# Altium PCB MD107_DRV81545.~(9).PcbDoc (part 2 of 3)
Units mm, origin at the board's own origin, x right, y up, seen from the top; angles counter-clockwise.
Board outline 152.45 x 74.46 mm, 4 copper layers (Top Layer, Mid-Layer 1, Mid-Layer 2, Bottom Layer), stack 2.355 mm thick; 223 components, 122 nets, 703 pads, 225 vias.
Unrouted connection lines stored in the file: 85.

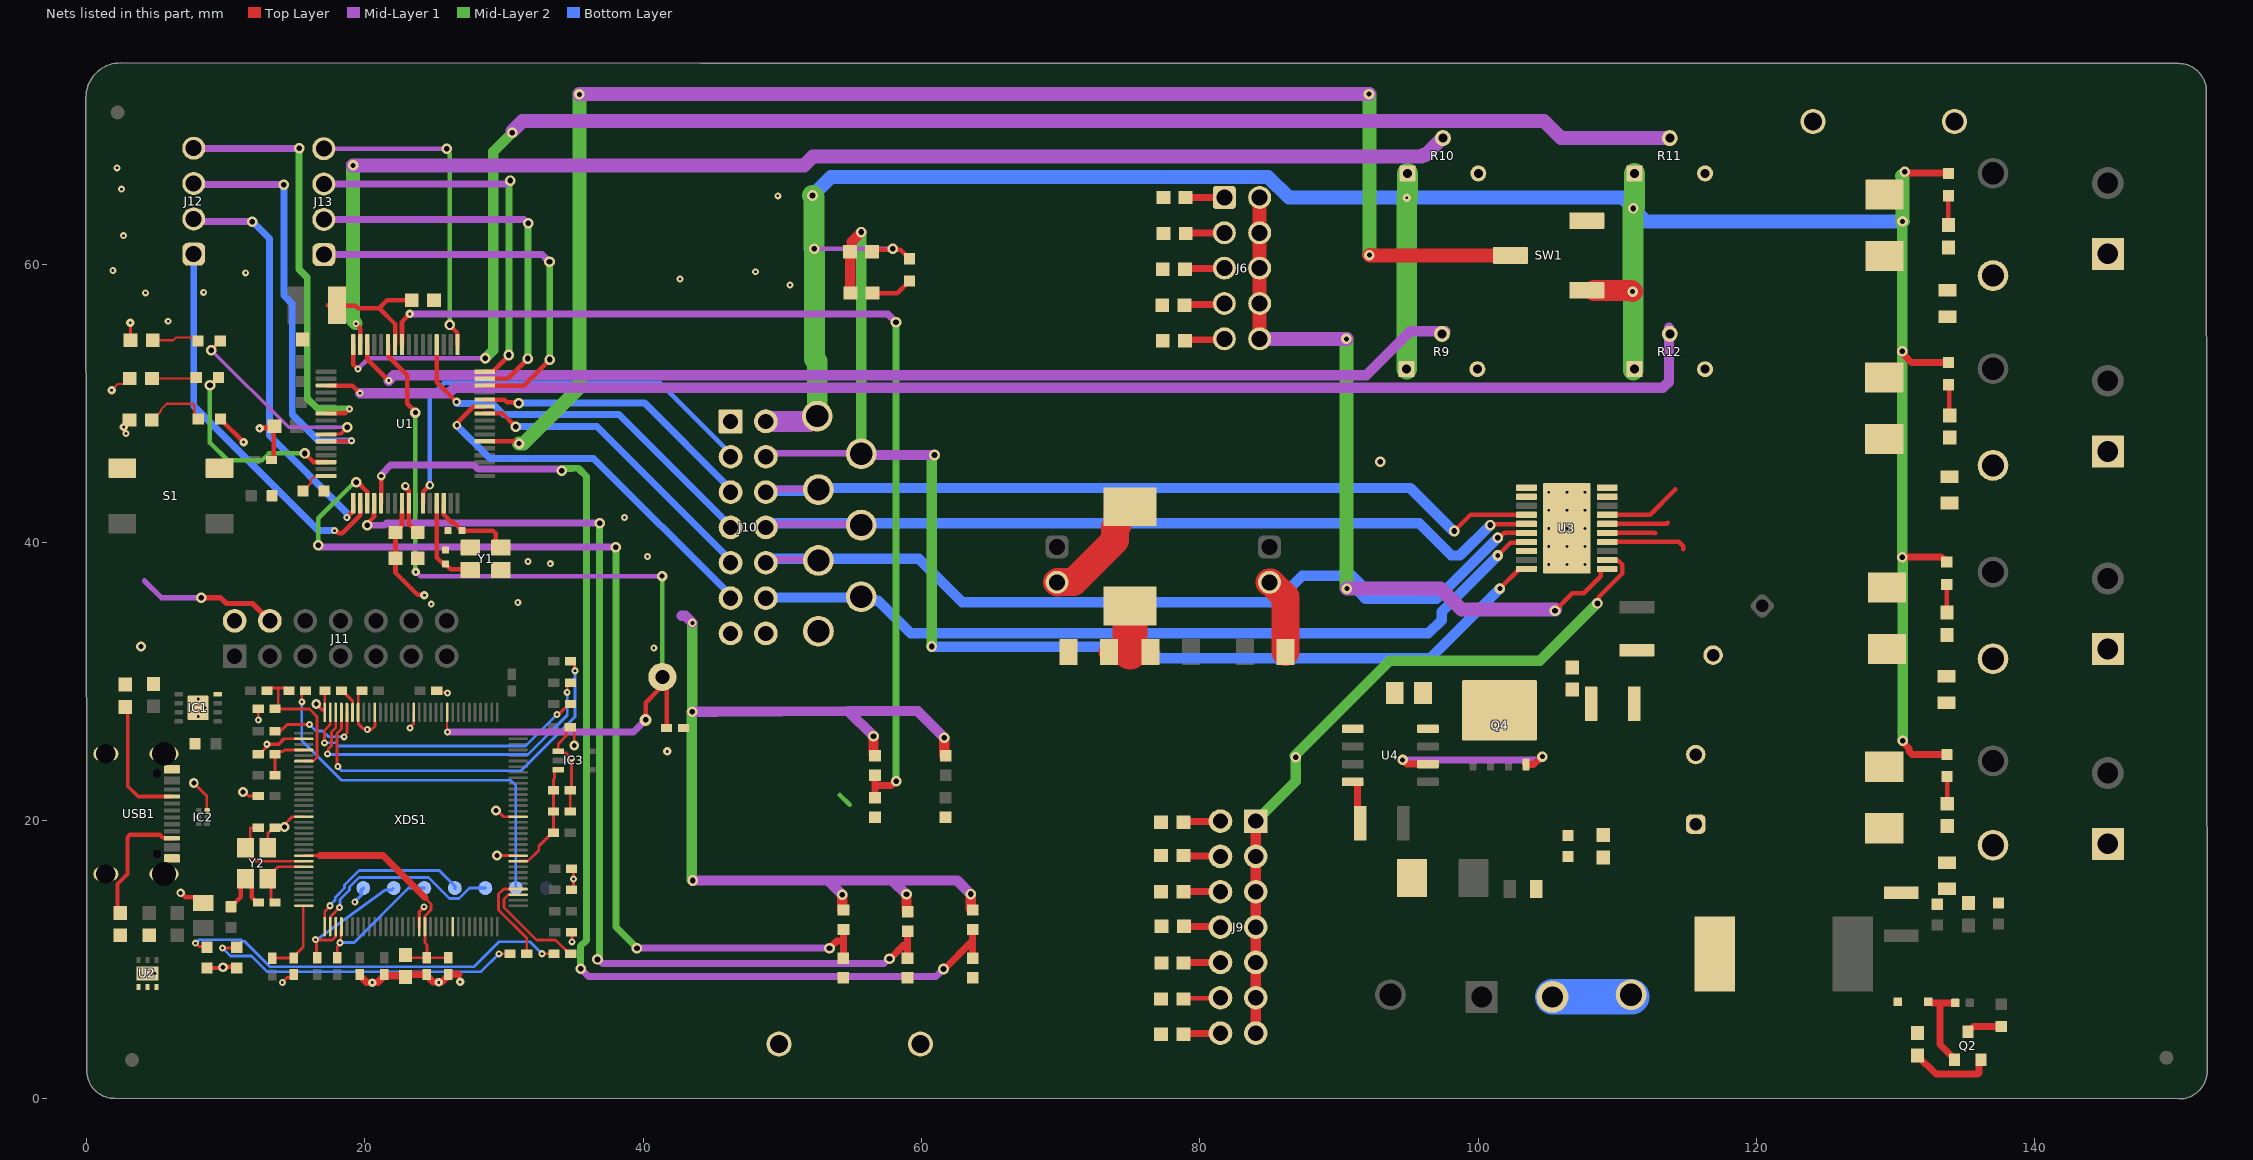
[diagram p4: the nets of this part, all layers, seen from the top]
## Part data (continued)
C50: library part CMP-0119409-1, "WCAP-CSGP Multilayer Ceramic Chip Capacitor, General Purpose, size 0603, X7R, 1nF, 100VDC", Capacitance Tolerance=+/-10%, Insulation Resistance=10GOhm, Manufacturer="Wurth Elektronik", Operating Temperature Max=125°C, Operating Temperature Min=-55°C, Rated Voltage (DC)=100V
D1 D2 D3 D13 D14 D15 D16 D18: library part CMP-0002894-2, "LED, Green, SMD", Color=green, Manufacturer="Wurth Elektronik", Value1=W, Value2=2V
D4: library part CMP-0078131-2, "LED, Red, SMD", Color=Red, Manufacturer=Lite-On, Power_TotalModule=62.5mW, Value1=.0625W, Value2=2V
D5: library part CMP-0002827-3, "LED, Green, SMD", Color=green, Manufacturer=Lite-On, Power_TotalModule=100mW, Value1=0.1W, Value2=2.1V
D6: library part CMP-0002947-3, "LED, Red, SMD", Color=Red, Manufacturer="Wurth Elektronik", Power_TotalModule=72mW, Value1=0.072W, Value2=2V
D7: library part CMP-0005695-3, "Diode, TVS, Bi, 33 V, SMC", Manufacturer=Bourns, Value1=1500W
D8: library part CMP-0005587-3, "Diode, TVS, Bi, 70 V, SMB", Manufacturer="Diodes Inc.", Value1=600W
D9 D10 D11 D12: library part CMP-0005564-3, "Diode, TVS, Bi, 33 V, SMB", Manufacturer="Diodes Inc.", Value1=600W
D17: library part CMP-14400-000003-2, "DIODE ZENER 4.7V 550MW SOD323F"
FID1 FID2 FID3: library part CMP-0077181-1, "Fiducial mark.  There is nothing to buy or mount.", Manufacturer=N/A
IC1: library part CMP-0036329-3, "500mA, Adjustable, Low Quiescent Current, Low-Noise, High-PSRR, Single-Output LDO Regulator, DRB0008A (VSON-8)", Manufacturer="Texas Instruments", Operating Temperature Range="-40 to 125 C", Rating=Catalog
IC2: library part CMP-0043115-3, "4-Channel ESD Protection Array for High-Speed Data Interfaces, DRY0006A (USON-6)", Breakdown Voltage(Min)(V)=6, IO Capacitance(Typ)(pF)=1.6, IO Leakage Current(nA)=1, Manufacturer="Texas Instruments", Operating Temperature Range="-40 to 85 C", Rating=Catalog
IC3: library part CMP-0032790-2, "Precision Micropower Shunt Voltage Reference, 0.5% accuracy, 2.5 V, 15 ppm / degC, 15 mA, -40 to 85 degC, 5-pin SC70 (DCK), Green (RoHS & no Sb/Br)", Manufacturer="Texas Instruments", Rating=Catalog, Temp Coeff(Max)(ppm/ degree C)=100, Temp Coeff(Typ)(ppm/ degree C)=15
J1 J2 J3 J4 J5: library part CMP-0121282-1, "2 Position Wire to Board Terminal Block Horizontal with Board 0.200\" (5.08mm) Through Hole", Current_A=20A, Digikey Part Number=732-10995-ND, Manufacturer="Wurth Electronics", Mouser Part Number=710-691236510002, Operating Temperature Range="-30°C to +120°C", Voltage_V=300V
J6: library part CMP-0054806-3, "Header, 2.54 mm, 5x2, Gold, TH", Current_A=3A, Manufacturer="Wurth Elektronik", Supplier Part Number 1=732-2672-ND, Voltage_V=250V
J7 J8: library part CMP-0054794-2, "Header, 2.54 mm, 2x1, Gold, TH", Color=Black, Manufacturer="Wurth Elektronik", Supplier Part Number 1=732-5315-ND
J9 J10 J11: library part CMP-0097334-1, "Connector Header Through Hole 14 position 0.100\" (2.54mm)", Current_A=3A, Digikey Part Number=732-5298-ND, Manufacturer="Wurth Electronics", Mouser Part Number=710-61301421121, Operating Temperature Range="-40°C to +105°C", Voltage_V=250V
J12 J13: library part CMP-0054798-2, "Header, 2.54 mm, 4x1, Gold, TH", Color=Black, Manufacturer="Wurth Elektronik", Supplier Part Number 1=732-5317-ND
L1: library part CMP-0063986-1, "Inductor, Shielded Drum Core, Ferrite, 1 uH, 24 A, 0.0012 ohm, SMD", Manufacturer="Wurth Elektronik", Supplier Part Number 1=732-2138-1-ND, Value1="0.0012 ohm", Value2=24A, ValueDisplayed=1uH
L3: library part CMP-0003267-2, "Ferrite Bead, 600 ohm @ 100 MHz, 0.5 A, 0603", Manufacturer="Wurth Elektronik", Supplier Part Number 1=732-2389-1-ND, Value1="0.35 ohm", Value2=0.5A, ValueDisplayed=600Ω
Logo1: library part CMP-0074844-2, Manufacturer="Texas Instruments"
Logo2: library part CMP-0074838-1, "Texas Instrument Corporate Signature"
Logo3: library part CMP-0074847-1, "FCC_disclaimer"
Logo4: library part CMP-0074769-4, Manufacturer="Texas Instruments"
LOGO5: library part CMP-0074837-2, "IEC 61010-1 Hot Surface Warning", Manufacturer="Texas Instruments"
Logo6: library part CMP-0074836-1, "IEC 61010-1 Caution Warning"
MP1 MP2 MP3 MP4: library part CMP-0122650-1, "Bumper Cylindrical, Dome 0.720\" Dia (18.30mm) Polyurethane Black", Digikey Part Number=RPC4835-ND, Manufacturer="Essentra Components", Mouser Part Number=144-RBS-37BK, Operating Temperature Range="32°F to 122°F"
Q2: library part CMP-1048-00779-1, "General Purpose Transistor, NPN Silicon, 3-Pin SOT-23, Pb-Free, Tape and Reel", Manufacturer="On Semiconductor"
Q4: library part CMP-0000915-2, "MOSFET, N-CH, 80 V, 100 A, DNK0008A (VSON-CLIP-8)", Alternate Manufacturer=None, Manufacturer="Texas Instruments", Supplier Part Number 1=296-37194-1-ND, Value2="48 nC"
R1 R2 R3 R34: library part CMP-0025912-5, "RES, 330, 5%, 0.1 W, 0603", Manufacturer=Yageo, Power_W=100mW, Supplier Part Number 1=311-330GRCT-ND, TempCo="100 ppm/C", Tolerance_%=5%, Value2=0.1W, Value_Code=330R, ValueDisplayed=330
R4: library part CMP-0083496-1, "RES, 20 k, 5%, 0.5 W, 1210", Manufacturer=Yageo, Power_W=500mW, TempCo="100 ppm/C", Tolerance_%=5%, Value2=0.5W, Value_Code=20k0, ValueDisplayed=20k
R5: library part CMP-0025899-5, "RES, 1.0 k, 5%, 0.1 W, 0603", Manufacturer=Yageo, Power_W=100mW, Supplier Part Number 1=311-1.0KGRCT-ND, TempCo="100 ppm/C", Tolerance_%=5%, Value2=0.1W, Value_Code=1k00, ValueDisplayed=1.0k
R6 R7: library part CMP-0025885-5, "RES, 0, 5%, 0.1 W, 0603", Manufacturer=Yageo, PartNumber=RC0603JR-070RL, Power_W=100mW, Supplier Part Number 1=311-0.0GRCT-ND, TempCo="200 ppm/C", Tolerance_%=5%, Value2=0.1W, Value_Code=0000, ValueDisplayed=0
R8 R32: library part CMP-0026935-3, "RES, 47 k, 5%, 0.063 W, AEC-Q200 Grade 0, 0402", Manufacturer=Vishay-Dale, Power_W=63mW, Supplier Part Number 1=541-47KJCT-ND, TempCo="200 ppm/C", Tolerance_%=5%, Value2=0.063W, Value_Code=47k0, ValueDisplayed=47k
R9 R10 R11 R12: library part CMP-0091455-1, "Res Cermet Trimmer 100K Ohm 10% 1/2W 1(Elec)/1(Mech)Turn 5mm (6.71 X 7.04 X 14.63mm) Pin Thru-Hole Tube", Digikey Part Number=3362P-1-104TLF-ND, Manufacturer=Bourns, Mouser Part Number=652-3362P-1-104TLF, Operating Temperature Range="-55°C to +125°C", Power_W=0.5W, TempCo=100ppm/°C, Tolerance_%=10%
R13 R23: library part CMP-0025932-5, "RES, 5.1 k, 5%, 0.1 W, 0603", Manufacturer=Yageo, Power_W=100mW, Supplier Part Number 1=311-5.1KGRCT-ND, TempCo="100 ppm/C", Tolerance_%=5%, Value2=0.1W, Value_Code=5k10, ValueDisplayed=5.1k
R14 R25 R26: library part CMP-0026825-5, "RES, 10 k, 5%, 0.063 W, AEC-Q200 Grade 0, 0402", Manufacturer=Vishay-Dale, Power_W=63mW, Supplier Part Number 1=541-10KJCT-ND, TempCo="200 ppm/C", Tolerance_%=5%, Value2=0.063W, Value_Code=10k0, ValueDisplayed=10k
R15 R24: library part CMP-0026824-3, "RES, 100, 5%, 0.063 W, AEC-Q200 Grade 0, 0402", Manufacturer=Vishay-Dale, Power_W=63mW, Supplier Part Number 1=541-100JCT-ND, TempCo="200 ppm/C", Tolerance_%=5%, Value2=0.063W, Value_Code=100R, ValueDisplayed=100
R16: library part CMP-0026413-2, "RES, 4.87 k, 1%, 0.063 W, AEC-Q200 Grade 0, 0402", Manufacturer=Vishay-Dale, Power_W=63mW, Supplier Part Number 1=541-4.87KLCT-ND, TempCo="100 ppm/C", Tolerance_%=1%, Value2=0.063W, Value_Code=4k87, ValueDisplayed=4.87k
R17: library part CMP-0026695-1, "RES, 3.30 k, 1%, 0.1 W, AEC-Q200 Grade 0, 0402", Manufacturer=Panasonic, Power_W=100mW, Supplier Part Number 1=P3.30KLCT-ND, TempCo="100 ppm/C", Tolerance_%=1%, Value2=0.1W, Value_Code=3k30, ValueDisplayed=3.30k
R18 R19 R20 R21 R28: library part CMP-0026852-3, "RES, 1.0 k, 5%, 0.063 W, AEC-Q200 Grade 0, 0402", Manufacturer=Vishay-Dale, Power_W=63mW, Supplier Part Number 1=541-1.0KJCT-ND, TempCo="200 ppm/C", Tolerance_%=5%, Value2=0.063W, Value_Code=1k00, ValueDisplayed=1.0k
R22: library part CMP-0026946-3, "RES, 51, 5%, 0.063 W, AEC-Q200 Grade 0, 0402", Manufacturer=Vishay-Dale, Power_W=63mW, Supplier Part Number 1=541-51JCT-ND, TempCo="200 ppm/C", Tolerance_%=5%, Value2=0.063W, Value_Code=51R0, ValueDisplayed=51
R27 R31: library part CMP-0026934-3, "RES, 470, 5%, 0.063 W, AEC-Q200 Grade 0, 0402", Manufacturer=Vishay-Dale, Power_W=63mW, Supplier Part Number 1=541-470JCT-ND, TempCo="200 ppm/C", Tolerance_%=5%, Value2=0.063W, Value_Code=470R, ValueDisplayed=470
R29: library part CMP-0026731-1, "RES, 330 k, 1%, 0.0625 W, 0402", Manufacturer="Yageo America", Power_W=62.5mW, Supplier Part Number 1=311-330KLRCT-ND, TempCo="100 ppm/C", Tolerance_%=1%, Value2=0.0625W, Value_Code=330k
R30: library part CMP-0026728-1, "RES, 220 k, 1%, 0.0625 W, 0402", Manufacturer="Yageo America", Power_W=62.5mW, Supplier Part Number 1=311-220KLRCT-ND, TempCo="100 ppm/C", Tolerance_%=1%, Value2=0.0625W, Value_Code=220k
R33: library part CMP-0023155-5, "RES, 4.99 k, 1%, 0.1 W, 0603", Manufacturer=Yageo, Power_W=100mW, Supplier Part Number 1=311-4.99KHRCT-ND, TempCo="100 ppm/C", Tolerance_%=1%, Value2=0.1W, Value_Code=4k99, ValueDisplayed=4.99k
R35 R36 R37 R38 R39 R40 R41 R42 R43 R44: library part CMP-0025886-5, "RES, 10 k, 5%, 0.1 W, 0603", Manufacturer=Yageo, Power_W=100mW, Supplier Part Number 1=311-10KGRCT-ND, TempCo="100 ppm/C", Tolerance_%=5%, Value2=0.1W, Value_Code=10k0, ValueDisplayed=10k
R45 R53: library part CMP-0022746-5, "RES, 10.0 k, 1%, 0.1 W, 0603", Manufacturer=Yageo, Power_W=100mW, Supplier Part Number 1=311-10.0KHRCT-ND, TempCo="100 ppm/C", Tolerance_%=1%, Value2=0.1W, Value_Code=10k0, ValueDisplayed=10.0k
R46 R56: library part CMP-0023212-5, "RES, 60.4 k, 1%, 0.1 W, 0603", Manufacturer=Yageo, Power_W=100mW, Supplier Part Number 1=311-60.4KHRCT-ND, TempCo="100 ppm/C", Tolerance_%=1%, Value2=0.1W, Value_Code=60k4, ValueDisplayed=60.4k
R47 R58: library part CMP-0022768-4, "RES, 120 k, 1%, 0.1 W, 0603", Manufacturer=Yageo, Power_W=100mW, Supplier Part Number 1=311-120KHRCT-ND, TempCo="100 ppm/C", Tolerance_%=1%, Value2=0.1W, Value_Code=120k
R48: library part CMP-0022844-4, "RES, 180 k, 1%, 0.1 W, 0603", Manufacturer=Yageo, Power_W=100mW, Supplier Part Number 1=311-180KHRCT-ND, TempCo="100 ppm/C", Tolerance_%=1%, Value2=0.1W, Value_Code=180k
R49 R59: library part CMP-0022937-4, "RES, 240 k, 1%, 0.1 W, 0603", Manufacturer=Yageo, Power_W=100mW, Supplier Part Number 1=311-240KHRCT-ND, TempCo="100 ppm/C", Tolerance_%=1%, Value2=0.1W, Value_Code=240k
R50 R51 R52: library part CMP-0086176-1, "RES, 0, 0.75 W, AEC-Q200 Grade 0, 1206", Manufacturer=Vishay-Dale, Power_W=750mW, Tolerance_%=0%, Value2=0.75W, Value_Code=0
R54: library part CMP-0023020-5, "RES, 30.0 k, 1%, 0.1 W, 0603", Manufacturer=Yageo, Power_W=100mW, Supplier Part Number 1=311-30.0KHRCT-ND, TempCo="100 ppm/C", Tolerance_%=1%, Value2=0.1W, Value_Code=30k0, ValueDisplayed=30.0k
R55: library part CMP-0023098-5, "RES, 40.2 k, 1%, 0.1 W, 0603", Manufacturer=Yageo, Power_W=100mW, Supplier Part Number 1=311-40.2KHRCT-ND, TempCo="100 ppm/C", Tolerance_%=1%, Value2=0.1W, Value_Code=40k2, ValueDisplayed=40.2k
R57: library part CMP-0023285-5, "RES, 80.6 k, 1%, 0.1 W, 0603", Manufacturer=Yageo, Power_W=100mW, Supplier Part Number 1=311-80.6KHRCT-ND, TempCo="100 ppm/C", Tolerance_%=1%, Value2=0.1W, Value_Code=80k6, ValueDisplayed=80.6k
R77 R78 R79 R80: library part CMP-0025922-5, "RES, 430, 5%, 0.1 W, 0603", Manufacturer=Yageo, Power_W=100mW, Supplier Part Number 1=311-430GRCT-ND, TempCo="100 ppm/C", Tolerance_%=5%, Value2=0.1W, Value_Code=430R, ValueDisplayed=430
R81: library part CMP-0097568-1, "47 kOhms ±1% 0.125W, 1/8W Chip Resistor 0402 (1005 Metric) Automotive AEC-Q200 Thick Film", Digikey Part Number=541-RCC040247K0FKEDCT-ND, Manufacturer="Vishay Dale", Mouser Part Number=71-RCC040247K0FKED, Operating Temperature Range="-55°C to +155°C", Power_W=125mW, TempCo=100ppm/°C, Tolerance_%=1%
R82: library part CMP-0023129-5, "RES, 470, 1%, 0.1 W, 0603", Manufacturer=Yageo, Power_W=100mW, Supplier Part Number 1=311-470HRCT-ND, TempCo="100 ppm/C", Tolerance_%=1%, Value2=0.1W, Value_Code=470R, ValueDisplayed=470
S1: library part CMP-0097347-1, "Tactile Switch SPST-NO Top Actuated Surface Mount", Coil Resistance_ohm=100mΩ, Contact Current Rating=50mA, Digikey Part Number=732-7022-1-ND, Manufacturer="Wurth Electronics", Mouser Part Number=710-430481025816, Operating Force=160gf, Operating Temperature Range="-40°C to +85°C"
SH1 SH2: library part CMP-0075110-1, "1mm Uninsulated Shorting Plug, 10.16mm spacing, TH", Manufacturer=Harwin, PartNumber=D3082-05, Supplier Part Number 1=952-1873-ND
SH-J1 SH-J2 SH-J3 SH-J4 SH-J5 SH-J6 SH-J7 SH-J8 SH-J10 SH-J11 SH-J12 SH-J14 SH-J15 SH-J16 SH-J17 SH-J18 SH-J19 SH-J20: library part CMP-0003761-2, "Shunt, 2.54mm, Gold, Black", Manufacturer="Wurth Elektronik", Supplier Part Number 1=732-2678-ND
SW1: library part CMP-0124534-1, "WS-SLSV SMT Mini Slide Switch Same Side Connection, 9.0 x 3.5 mm", Coil Resistance_ohm=70mΩ, Contact Current Rating=300mA, Manufacturer=Wurth, Operating Force=350gf, Operating Temperature Range="-40°C to +85°C"
TP1 TP2 TP3 TP4 TP5 TP6 TP7: library part CMP-0003825-1, "1mm Test Point, SMT", Manufacturer=Any, PartNumber=TP_SM_1MM
TP8: library part CMP-0055139-2, "Test Point, Miniature, White, TH", Color=White, Manufacturer="Keystone Electronics", Supplier Part Number 1=36-5002-ND
TP10: library part CMP-0055150-1, "Test Point, Multipurpose, Orange, TH", Color=Orange, Manufacturer=Keystone, Supplier Part Number 1=36-5013-ND
TP11 TP12 TP13 TP14 TP15 TP17 TP18 TP19 TP22: library part CMP-0055149-2, "Test Point, Multipurpose, White, TH", Color=White, Manufacturer="Keystone Electronics", Supplier Part Number 1=36-5012-ND
TP16 TP21 TP23 TP31 TP32: library part CMP-0055147-2, "Test Point, Multipurpose, Red, TH", Color=Red, Manufacturer="Keystone Electronics", Supplier Part Number 1=36-5010-ND
TP25 TP33: library part CMP-0055148-2, "Test Point, Multipurpose, Black, TH", Color=Black, Manufacturer="Keystone Electronics", Supplier Part Number 1=36-5011-ND
U1: library part CMP-0093960-1, "Mixed-Signal Microcontrollers With CAN-FD Interface LQFP64", Frequency_Fixed=80MHz, Manufacturer="Texas Instruments", Max Supply Voltage=3.6V, Min Supply Voltage=1.62V, Operating Temperature Range="-40°C to +125°C"
U2: library part CMP-0077837-1, "5-V Precision Surge Protection Clamp, DRV0006A (WSON-6)", Alternate Manufacturer="Texas Instruments"
U3: library part CMP-0125514-1, Manufacturer="Texas Instruments", Operating Temperature Range=to
U4: library part CMP-0125797-1, Manufacturer="Texas Instruments", Operating Temperature Range=to
USB1: library part CMP-0095999-2, "Conenctor USB 2.0 Type C Horizontal SMT", Current_A=5A, Manufacturer="Wurth Electronics", Operating Temperature Range="-40°C to +85°C", Voltage_V=20V
XDS1: library part CMP-0077954-1, "MSP432E401YTPDT, PDT0128A (TQFP-128)", Alternate Manufacturer="Texas Instruments", Alternate PartNumber=MSP432E401YTPDT
Y1: library part CMP-0098168-2, "Crystal 40MHz ±10ppm (Tol) ±20ppm (Stability) 12pF FUND 40Ohm 4-Pin Mini-CSMD T/R", Frequency Stability=20ppm, Frequency Tolerance=10ppm, Frequency_Fixed=40MHz, Load Capacitance=12pF, Manufacturer="Seiko Epson", Operating Temperature Range="-40°C to +105°C"
Y2: library part CMP-0004635-3, "Crystal, 16 MHz, 8pF, SMD", Frequency Stability=+/-30ppm, Frequency_Fixed=16MHz, Manufacturer=NDK, Supplier Part Number 1=644-1157-1-ND
ZZ1: library part CMP-0003616-3
ZZ2: library part CMP-0077236-1
ZZ3: library part CMP-0077237-1
ZZ4: library part CMP-0077238-1

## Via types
v1: diameter 0.762, hole 0.406, Top Layer to Bottom Layer, tented both sides, 64 vias
v2: diameter 0.508, hole 0.203, Top Layer to Bottom Layer, tented both sides, 46 vias
v3: diameter 0.5, hole 0.2, Top Layer to Bottom Layer, tented both sides, 38 vias
v4: diameter 0.762, hole 0.356, Top Layer to Bottom Layer, tented both sides, 17 vias
v5: diameter 0.61, hole 0.2, Top Layer to Bottom Layer, tented both sides, 11 vias
v6: diameter 0.762, hole 0.381, Top Layer to Bottom Layer, tented both sides, 10 vias
v7: diameter 0.61, hole 0.305, Top Layer to Bottom Layer, tented both sides, 9 vias
v8: diameter 0.711, hole 0.356, Top Layer to Bottom Layer, tented both sides, 9 vias
v9: diameter 0.61, hole 0.203, Top Layer to Bottom Layer, tented both sides, 6 vias
v10: diameter 0.5, hole 0.2, Top Layer to Bottom Layer, 6 vias
v11: diameter 0.61, hole 0.3, Top Layer to Bottom Layer, tented both sides, 4 vias
v12: diameter 0.762, hole 0.4, Top Layer to Bottom Layer, tented both sides, 2 vias
v13: diameter 0.914, hole 0.465, Top Layer to Bottom Layer, tented both sides, 2 vias
v14: diameter 0.864, hole 0.406, Top Layer to Bottom Layer, tented both sides, 1 vias

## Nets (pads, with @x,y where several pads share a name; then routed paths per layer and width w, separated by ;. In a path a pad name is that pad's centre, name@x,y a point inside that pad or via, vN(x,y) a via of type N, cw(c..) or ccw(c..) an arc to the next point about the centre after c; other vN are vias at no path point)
3V3: D6.2 D13.2 D14.2 D15.2 D16.2 J10.2 R9.1 R10.1 R11.1 R12.1 R33.2 SW1.1 TP10.1 | length 194.8
  Top Layer w0.326: R33.2@56.277,61.01 56.297,61.029 57.85,61.029 v1(57.934,61.113) 58.017,61.029 58.486,61.029 59.122,60.393 D6.2@59.213,60.393
  Top Layer w0.5: v1(130.489,53.728) 130.489,53.609 130.916,53.182 130.916,53.159 131.145,52.93 D14.2@133.813,52.93 ; v1(130.497,38.937) 133.296,38.937 133.416,38.817 133.455,38.817 133.654,38.618 D15.2@133.654,38.579 ; v1(130.529,25.739) 130.529,25.621 130.967,25.183 130.967,24.996 131.197,24.765 D16.2@133.716,24.765 ; v1(130.679,66.646) 130.75,66.646 130.854,66.542 133.665,66.542 133.69,66.567 D13.2@133.76,66.567
  Top Layer w1.5: SW1.1@108.325,58.105 111.028,58.105 v4(111.111,58.021)
  Mid-Layer 1 w0.326: v1(52.279,61.113) v1(57.934,61.113)
  Mid-Layer 1 w1.5: J10.2@48.776,48.785 48.869,48.692 51.929,48.692 52.313,49.076 TP10.1@52.505,49.076
  Mid-Layer 2 w0.75: v1@130.497,38.934 130.497,53.718 130.489,53.725 130.489,63.052 130.506,63.069 v4(130.506,63.072) ; v1(130.529,25.739) v1@130.529,38.902
  Mid-Layer 2 w1: v1@130.473,66.349 130.506,66.316 v4(130.506,63.072)
  Mid-Layer 2 w1.5: v1(52.167,64.932) 52.279,64.819 v1(52.279,61.113) 52.313,61.08 52.313,53.181 52.505,52.989 TP10.1@52.505,49.076 ; R9.1@94.876,52.454 v9(94.876,64.772) 94.94,64.835 R10.1@94.94,66.516 ; R12.1@111.158,52.387 111.158,57.975 v4(111.111,58.021) 111.144,58.053 v1(111.144,64.001) 111.241,64.098 R11.1@111.241,66.516
  Bottom Layer w1: v1(52.167,64.932) 53.503,66.267 84.918,66.267 86.414,64.772 v9(94.876,64.772) 110.372,64.772 112.072,63.072 v4(130.506,63.072)
3V3_MCU: C4.1 C5.1 D3.2 J10.1 J11.4 R7.1 R8.2 R35.1 R37.1 R39.1 R41.1 R43.1 U1.40 | length 93.9
  Top Layer w0.326: D3.2@9.614,48.858 11.288,47.184 v5@11.288,47.177 ; R8.2@13.274,45.924 13.302,45.924 13.439,46.061 R7.1@13.439,48.327 ; U1.40@22.662,42.227 22.662,41.18 22.532,41.051 22.532,41.026 22.22,40.714 C4.1@22.195,40.714 C5.1@22.195,38.862 22.195,37.822 23.778,36.239 24.229,36.239 v5(24.272,36.195)
  Top Layer w0.381: v6(8.226,36.022) 9.62,36.022 10.042,35.6 11.928,35.6 J11.4@13.168,34.359 ; v5(12.426,48.188) 12.47,48.232 13.338,48.232 R7.1@13.433,48.327
  Top Layer w0.75: v1(54.293,14.679) 54.315,14.657 R39.1@54.315,13.571 ; v1(56.552,26.063) 56.552,24.778 R35.1@56.596,24.734 ; R41.1@58.922,13.527 v1(58.922,14.701) ; v1(61.646,25.952) 61.646,24.712 R37.1@61.734,24.623 ; v1(63.55,14.723) 63.55,13.66 R43.1@63.617,13.593
  Mid-Layer 1 w0.381: 4.159,37.232 5.369,36.022 v6(8.226,36.022)
  Mid-Layer 1 w0.75: 42.777,34.726 43.015,34.726 v11(43.534,34.206) ; v1(43.528,27.823) 45.241,27.823 45.255,27.837 54.736,27.879 ; v1(43.551,15.697) 53.296,15.697 ; v1(54.293,14.679) 54.27,14.701 54.27,14.723 53.296,15.697 ; v1(56.552,26.063) 54.736,27.879 ; v1(58.922,14.701) 58.899,14.701 57.903,15.697 ; v1(61.646,25.952) 59.719,27.879 54.736,27.879 ; v1(63.55,14.723) 62.576,15.697 57.903,15.697 ; 53.296,15.697 57.903,15.697
  Mid-Layer 2 w0.75: v1@43.499,27.823 43.499,15.734 v1@43.543,15.691 ; v1(43.528,27.823) 43.528,34.2 v11(43.534,34.206)
  other v5: 11.27,47.212
+5V: J11.2
BSL_INVOKE: R32.2 TP8.1 U1.11 XDS1.42 | length 65.7
  Top Layer w0.152: XDS1.42@25.907,27.78 25.907,26.389 v3(25.924,26.372)
  Top Layer w0.326: U1.11@21.662,54.214 21.675,54.201 21.675,53.384 23.043,52.016 23.043,49.971 23.628,49.386 v4(23.628,49.325) ; v14(40.177,27.246) 40.177,28.483 41.05,29.356 41.05,30.001 TP8.1@41.377,30.328 41.681,30.023 R32.2@41.682,26.66
  Mid-Layer 1 w0.152: v14@40.163,27.232 v14@40.163,27.281
  Mid-Layer 1 w0.326: v9(23.655,37.876) 23.687,37.876 23.988,37.575 v4(41.355,37.575)
  Mid-Layer 1 w0.5: v3(25.924,26.372) 39.303,26.372 v14@40.163,27.232
  Mid-Layer 2 w0.326: v9@23.628,37.904 v4(23.628,49.325) ; v4@41.377,37.575 41.377,30.444 TP8.1@41.499,30.322
CC1: R13.1 USB1.A5 | length 9.2
  Top Layer w0.254: R13.1@2.766,28.172 2.962,27.977 2.962,22.471 3.698,21.734 USB1.A5@6.122,21.734
CC2: R23.1 USB1.B5 | length 9.2
  Top Layer w0.305: R23.1@2.406,13.362 2.207,13.561 2.207,15.456 2.923,16.172 2.923,18.806 3.102,18.984 5.245,18.984 5.45,18.779 5.593,18.779 5.636,18.737 6.12,18.737 USB1.B5@6.122,18.734
COD: J6.2 J6.4 J6.6 J6.8 J6.10 U3.11 | length 55.7
  Top Layer w0.326: v1(105.529,35.098) 106.774,36.343 107.591,36.343 108.815,37.567 108.815,38.02 108.908,38.113 U3.11@109.672,38.113
  Top Layer w1: J6.10@84.278,54.567 84.306,54.595 J6.10@84.306,54.63 J6.8@84.306,57.17 J6.6@84.306,59.71 J6.4@84.306,62.25 J6.2@84.306,64.79
  Mid-Layer 1 w1: J6.10@84.306,54.63 90.524,54.63 v4(90.532,54.623) ; v4(90.575,36.677) 97.299,36.677 98.813,35.164 v1@105.537,35.164
  Mid-Layer 2 w1: v4(90.532,54.623) 90.532,36.72 v4(90.575,36.677)
DEV_ID1: R39.2 R40.1 U1.35 | length 74.9
  Top Layer w0.326: v1(19.377,44.331) 19.431,44.276 19.517,44.276 20.149,43.644 U1.35@20.149,43.401
  Top Layer w0.5: v1(53.391,10.84) 53.908,11.358 54.383,11.358 ; R40.1@54.354,10.254 54.383,10.284 54.383,11.358 ; R39.2@54.387,12.168 54.383,12.164 54.383,11.358
  Mid-Layer 1 w0.5: v1(16.648,39.8) 16.678,39.8 16.799,39.679 38.007,39.679 v1(38.027,39.659) ; v1(39.548,10.84) v1(53.391,10.84)
  Mid-Layer 2 w0.326: v1(16.648,39.8) 16.648,41.724 19.211,44.286 19.332,44.286 v1(19.377,44.331)
  Mid-Layer 2 w0.5: v1(38.027,39.659) 38.027,12.36 v1(39.548,10.84)
DEV_ID2: R41.2 R42.1 U1.36 | length 74.2
  Top Layer w0.326: v1(20.171,41.23) 20.171,41.348 20.649,41.826 U1.36@20.649,42.227
  Top Layer w0.5: v1(57.7,10.066) 57.742,10.066 58.755,11.079 59.007,11.079 ; R42.1@58.947,10.181 59.007,10.242 59.007,11.079 ; R41.2@59.009,12.053 59.007,12.051 59.007,11.079
  Mid-Layer 1 w0.5: v1(20.171,41.23) 21.406,41.23 21.552,41.376 36.861,41.376 v1(36.864,41.378) ; v1(36.709,10.025) 36.78,10.025 37.06,9.745 57.308,9.745 57.629,10.066 v1(57.7,10.066)
  Mid-Layer 2 w0.5: v1(36.709,10.025) 36.709,10.096 36.864,10.25 v1(36.864,41.378)
DEV_ID3: R43.2 R44.1 U1.37 | length 84.3
  Top Layer w0.326: U1.37@21.162,42.814 v7(21.162,44.763)
  Top Layer w0.5: v1(61.578,9.336) 61.647,9.336 63.678,11.366 ; R43.2@63.678,12.168 63.678,11.366 ; R44.1@63.79,10.358 63.691,10.358 63.678,10.371 63.678,11.366
  Mid-Layer 1 w0.5: v7@21.212,44.923 21.845,45.556 27.814,45.556 28.112,45.258 v1@34.152,45.258 ; v1(35.501,9.36) 36.074,8.787 61.029,8.787 v1(61.578,9.336)
  Mid-Layer 2 w0.5: v1@34.152,45.258 34.223,45.187 34.267,45.187 34.388,45.308 34.895,45.308 34.914,45.328 35.329,45.328 35.914,44.742 35.914,11.388 35.501,10.975 v1(35.501,9.36)
  other v1: 34.146,45.137
GND: C2.2 C3.1 C4.2 C5.2 C6.1 C7.1 C8.2 C9.2 C10.2 C11.2 C12.2 C13.2 C14.2 C15.2 C16.2 C17.2 C18.2 C19.2 C20.2 C21.2 C22.2 C23.2 C24.2 C25.2 C26.2 C27.2 C28.2 C29.2 C30.1 C31.1 C33.2 C34.1 C35.1 C36.1 C37.1 C39.2 C40.1 C41.1 C42.1 C43.2 C44.1 C45.2 C46.1 C48.1 C49.1 C50.1 D4.2 D5.2 D8.1 D9.1 D10.1 D11.1 D12.1 D17.2 IC1.4 IC1.9 IC2.3 IC3.1 J5.2 J10.13 J10.14 R1.1 R2.1 R3.1 R5.1 R6.1 R9.3 R10.3 R11.3 R12.3 R13.2 R16.1 R23.2 R30.1 R32.1 R36.2 R38.2 R40.2 R42.2 R44.2 R45.1 R46.1 R47.1 R48.1 R49.1 R50.1 R53.1 R54.1 R55.1 R56.1 R57.1 R58.1 R59.1 R82.1 S1.3 S1.4 SH1.1 SH1.2 SH2.1 SH2.2 SW1.3 TP1.1 TP25.1 TP33.1 U1.41 U2.1 U2.2 U2.3 U2.7@4.364,9.014 U3.1 U3.2 U3.8 U3.19 U3.20 U3.21 U4.1 USB1.1 USB1.2 USB1.3 USB1.4 USB1.A1-B12 USB1.A12-B1 XDS1.10 XDS1.17 XDS1.48 XDS1.55 XDS1.58 XDS1.64 XDS1.66 XDS1.80 XDS1.114 Y1.2 Y1.4 Y2.2 Y2.4 | length 70.9
  Top Layer w0.152: v5(1.788,50.93) 2.237,51.379 2.693,51.379 R2.1@3.092,51.778 ; R32.1@42.782,26.66 R32.1@42.882,26.66
  Top Layer w0.203: v3@2.66,47.832 v9(2.66,48.291) 3.074,48.706 R3.1@3.074,48.797 ; R1.1@3.118,54.498 R1.1@3.145,54.525 3.137,54.532 v5(3.137,55.785) ; v8(7.697,22.7) 8.632,21.765 8.632,20.83 8.644,20.818 IC2.3@8.594,20.818 ; v8(11.242,22.062) 11.334,22.062 11.624,21.772 C15.2@12.329,21.772 ; C8.2@12.273,28.03 12.335,27.968 v2(12.335,27.243) ; C12.2@12.329,24.78 12.429,24.78 12.886,25.237 12.886,25.432 v2(12.944,25.491) v2@12.886,25.549 ; Y2.2@13.01,18.039 13.01,19.069 13.429,19.488 C16.2@13.529,19.488 13.55,19.509 14.203,19.509 v8(14.225,19.53) 14.322,19.627 14.322,19.832 14.77,20.28 XDS1.80@15.607,20.28 ; v2(14.058,8.377) 14.416,8.734 14.682,8.734 14.88,8.933 C24.2@14.88,8.935 ; 14.163,25.872 14.172,25.88 XDS1.66@15.607,25.88 ; XDS1.64@17.107,27.78 XDS1.64@17.107,27.978 ; XDS1.64@17.107,28.379 R16.1@17.107,29.323 ; C9.2@19.742,29.482 19.717,29.482 19.519,29.283 19.519,27.169 19.521,27.167 19.521,26.966 19.879,26.607 20.112,26.607 v2(20.17,26.549) 20.171,26.55 20.481,26.55 20.719,26.788 20.719,27.172 XDS1.55@20.709,27.182 ; v2(23.236,26.652) 23.236,26.707 23.507,26.978 XDS1.48@23.507,27.78 ; C10.2@25.157,29.336 25.261,29.232 25.865,29.232 v2(25.924,29.174) ; v8@29.48,17.489 XDS1.10@31.018,17.489 ; v8@29.51,20.715 29.945,20.28 XDS1.17@31.007,20.28 ; C18.2@34.756,20.651 C17.2@34.756,22.174 34.844,22.262 v2(34.844,24.479) 34.449,24.874 33.99,24.874 IC3.1@33.892,24.972 33.892,25.508 34.458,26.074 34.458,26.511 34.656,26.709 C11.2@34.756,26.709 34.844,26.709 35.042,26.511 v8(35.042,25.414) ; R30.1@34.844,11.976 34.89,11.931 v2(34.89,11.292) ; C20.2@34.844,15.022 34.991,15.17 v2(34.991,15.813) 34.991,16.398 C19.2@34.844,16.545
  Top Layer w0.254: v2(12.944,25.491) 13.8,25.491 14.172,25.863 ; v8(16.5,28.386) 16.909,27.978 XDS1.64@17.08,27.978 ; XDS1.114@23.907,12.38 23.907,13.461 24.247,13.801 v2(24.247,13.807) ; v8(29.429,20.715) v8@29.51,20.715
  Top Layer w0.305: D4.2@8.753,9.349 8.81,9.406 9.738,9.406 v8(9.795,9.463) 9.838,9.506 10.742,9.506 D5.2@10.785,9.549
  Top Layer w0.326: v7(6.75,14.808) 6.827,14.808 7.13,14.505 8.042,14.505 C14.2@8.354,14.193 ; C22.2@10.369,13.815 11.067,14.513 11.067,15.731 Y2.4@11.292,15.956 ; Y2.4@11.41,15.839 11.847,15.402 11.847,14.506 12.238,14.115 C23.2@12.362,14.115 ; v7(22.907,44.05) 22.907,43.973 23.147,43.733 U1.41@23.147,43.147 ; U1.41@23.141,43.147 23.141,41.343 23.77,40.714 C4.2@23.795,40.714
  Top Layer w0.508: C25.2@19.637,8.949 19.637,8.849 20.108,8.379 20.504,8.379 v9(20.524,8.36) 20.543,8.379 20.917,8.379 21.387,8.849 C26.2@21.387,8.949 21.387,8.895 21.433,8.849 22.819,8.849 C27.2@22.919,8.749 ; C27.2@22.919,8.949 C28.2@24.452,8.949 24.452,8.849 24.905,8.396 25.277,8.396 v9(25.297,8.377) 25.316,8.396 25.532,8.396 25.985,8.849 C29.2@25.985,8.949 26.749,8.949 26.769,8.93
  Mid-Layer 2 w0.326: 54.13,21.842 54.831,21.14
  Bottom Layer w0.254: v2(19.269,14.162) 19.736,14.629 19.736,15.01 TP1.1@19.878,15.153
  Bottom Layer w2.54: J5.2@105.347,7.333 111.041,7.333 TP25.1@111.046,7.338
  other v1: 92.984,45.783
  other v3: 40.763,32.399 24.763,35.56 30.984,35.679 105.085,38.407 106.385,38.407 107.685,38.407 33.323,38.466 31.71,38.629 40.315,38.992 105.085,39.707 106.385,39.707 107.685,39.707 105.085,41.007 106.385,41.007 107.685,41.007 38.653,41.788 105.085,42.307 106.385,42.307 107.685,42.307 105.085,43.607 106.385,43.607 107.685,43.607 2.819,47.832 5.855,55.892 4.22,57.936 8.409,57.973 50.546,58.505 42.651,58.934 11.428,59.373 48.069,59.451 1.875,59.543 2.64,62.041 49.673,64.909 2.511,65.382 2.182,66.918
  other v5: 41.722,24.973
  other v8: 29.48,17.49 3.892,32.523
  other v9: 26.842,8.411
  other v10: 3.814,9.014 4.914,9.014 8.011,27.482 7.511,28.107 8.511,28.107 8.011,28.732
GUI_STATUS: D2.2 U1.30 | length 14.3
  Top Layer w0.326: v1(8.86,51.282) 8.916,51.282 9.42,51.787 D2.2@9.464,51.787 ; v1(15.682,46.392) 16.297,45.777 17.199,45.777 U1.30@17.212,45.764
  Mid-Layer 2 w0.326: v1(8.86,51.282) 8.86,47.172 10.136,45.896 12.602,45.896 13.098,46.392 v1(15.682,46.392)
HFXIN: C7.2 U1.45 Y1.3 | length 6.5
  Top Layer w0.326: U1.45@25.162,42.814 25.162,38.91 C7.2@25.675,38.397 ; C7.2@25.793,38.448 26.169,38.071 Y1.3@27.472,38.071
HFXOUT: C6.2 U1.46 Y1.1 | length 6.2
  Top Layer w0.326: U1.46@25.662,42.814 25.675,42.801 25.675,41.984 26.203,41.456 26.362,41.456 C6.2@26.953,40.864 ; C6.2@26.977,40.841 29.199,40.841 29.4,40.639 29.4,39.964 Y1.1@29.714,39.65
HW/GUI: SW1.2 U1.54 | length 107.5
  Top Layer w0.326: U1.54@29.199,47.264 30.799,47.264 30.967,47.096 v4(31.085,47.096)
  Top Layer w1: v4(92.186,60.65) 92.214,60.623 SW1.2@102.325,60.623
  Mid-Layer 1 w1: v4(35.405,72.194) 35.429,72.218 v4(92.162,72.218)
  Mid-Layer 2 w1: v4(31.085,47.096) 31.385,47.096 35.405,51.117 v4(35.405,72.194) ; v4(92.162,72.218) 92.186,72.193 v4(92.186,60.65)
ILIM: J9.1 J9.3 J9.5 J9.7 J9.9 J9.11 J9.13 U3.12 | length 52.5
  Top Layer w0.326: v1(108.581,35.612) 108.664,35.695 108.664,36.069 110.351,37.755 110.351,38.408 110.089,38.67 108.921,38.67 U3.12@108.856,38.734
  Top Layer w0.75: J9.1@83.931,19.949 84.026,19.854 J9.9@84.026,9.808 J9.11@84.026,7.268 J9.13@84.026,4.728
  Mid-Layer 2 w0.75: J9.1@84.026,19.968 86.891,22.833 v1(86.891,24.555) ; v1@86.822,24.656 93.648,31.482 104.451,31.482 v1(108.581,35.612)
IN1: J10.6 TP13.1 U3.4 | length 60.2
  Top Layer w0.326: v1@98.234,40.849 98.329,40.849 99.461,41.982 U3.4@103.485,41.982
  Mid-Layer 1 w0.5: J10.6@48.801,43.849 52.538,43.849 TP13.1@52.592,43.794
  Bottom Layer w0.75: J10.6@48.946,43.703 52.501,43.703 52.705,43.907 95.131,43.907 98.221,40.817 v1(98.297,40.817)
IN2: J10.8 TP15.1 U3.5 | length 64.1
  Top Layer w0.326: v1(100.887,41.245) 100.931,41.288 103.89,41.288 U3.5@103.911,41.309
  Mid-Layer 1 w0.5: J10.8@48.742,41.367 48.804,41.306 55.665,41.306 TP15.1@55.697,41.338
  Bottom Layer w0.75: J10.8@48.742,41.367 95.773,41.367 98.082,39.058 98.704,39.058 100.887,41.241 v1(100.887,41.245)
IN3: J10.10 TP12.1 U3.6 | length 63.7
  Top Layer w0.326: v1(101.417,40.339) 101.535,40.339 101.877,40.682 U3.6@103.485,40.682 103.945,40.682 U3.6@103.959,40.696
  Mid-Layer 1 w0.5: J10.10@48.742,38.827 48.807,38.763 52.148,38.763 TP12.1@52.318,38.933
  Bottom Layer w0.75: J10.10@49.025,38.827 52.592,38.827 59.803,38.827 62.933,35.697 85.489,35.697 87.378,37.585 90.951,37.585 91.483,37.053 91.483,36.367 91.923,35.928 97.005,35.928 v1(101.417,40.339)
IN4: J10.12 TP14.1 U3.7 | length 59.3
  Top Layer w0.326: v4(101.417,39.055) 102.332,39.97 103.797,39.97 U3.7@103.854,40.027
  Bottom Layer w0.75: J10.12@48.815,35.992 48.86,36.038 55.644,36.038 55.676,36.07 TP14.1@55.663,36.083 55.942,35.804 56.889,35.804 59.228,33.466 96.438,33.466 97.388,34.415 97.388,35.026 v4(101.417,39.055)
IRSTN: R15.1 TP6.1 | length 27.8
  Top Layer w0.203: v2(15.459,28.539) 15.459,29.148 R15.1@15.662,29.351
  Bottom Layer w0.203: v2(15.459,28.539) 15.459,25.763 18.322,22.9 30.47,22.9 30.843,22.527 TP6.1@30.843,15.153
ITCK: R26.2 TP3.1 XDS1.100 | length 10.4
  Top Layer w0.203: R26.2@18.011,10.149 18.011,10.938 v2@18.208,11.136 ; v2(18.211,11.221) 18.261,11.271 18.261,12.088 18.297,12.124 XDS1.100@18.297,12.858
  Bottom Layer w0.203: v2@18.27,11.249 19.233,11.249 23.138,15.153 TP3.1@24.264,15.153 TP3.1@24.273,15.153
ITDI: TP5.1 XDS1.98 | length 14.4
  Top Layer w0.203: XDS1.98@17.507,12.38 17.507,13.081 18.177,13.75 v2(18.177,13.756)
  Bottom Layer w0.203: v2(18.177,13.756) 18.215,13.795 18.215,14.332 18.891,15.007 18.891,15.231 19.566,15.907 21.501,15.907 24.576,15.907 26.084,14.399 26.769,14.399 27.523,15.153 TP5.1@28.65,15.153
ITDO: TP4.1 XDS1.97 | length 12
  Top Layer w0.203: XDS1.97@17.107,12.979 17.107,13.476 17.491,13.859 v2(17.491,13.883)
  Bottom Layer w0.203: v2(17.491,13.883) 17.491,13.935 17.86,14.304 17.86,14.479 18.535,15.154 18.535,15.379 19.579,16.423 25.339,16.423 26.482,15.28 TP4.1@26.482,15.102
ITMS: R25.2 TP2.1 XDS1.99 | length 10.9
  Top Layer w0.203: v2(16.45,11.445) 16.468,11.426 17.654,11.426 17.905,11.677 XDS1.99@17.905,12.965 ; v2@16.508,11.328 16.508,10.217 R25.2@16.576,10.149 ; R25.2@16.567,10.135 R25.2@16.567,10.149
  Bottom Layer w0.203: v2@16.443,11.397 16.471,11.416 21.473,15.02 21.93,15.02 TP2.1@22.024,15.114
MCU_IN1: J10.5 U1.60 | length 20.2
  Top Layer w0.326: U1.60@28.612,50.264 28.625,50.251 30.028,50.251 30.194,50.085 30.977,50.085 v12(31.061,50.001)
  Bottom Layer w0.5: v12(31.061,50.001) 40.108,50.001 46.097,44.013 J10.5@46.188,44.013
MCU_IN2: J10.7 U1.4 | length 27.2
  Top Layer w0.326: U1.4@25.162,53.627 25.162,51.513 v7(26.583,50.092)
  Bottom Layer w0.5: v7@26.571,49.974 29.172,49.974 29.96,49.186 38.254,49.186 46.087,41.353 J10.7@46.117,41.353
MCU_IN3: J10.9 U1.58 | length 22.1
  Top Layer w0.326: U1.58@28.612,49.264 29.888,49.264 v12(30.832,48.32)
  Bottom Layer w0.5: v12(30.832,48.32) 36.678,48.32 46.129,38.87 J10.9@46.366,38.87
MCU_IN4: J10.11 U1.59 | length 27.2
  Top Layer w0.326: v7(26.61,48.414) 26.664,48.468 26.664,48.633 27.782,49.751 28.599,49.751 U1.59@28.612,49.764
  Bottom Layer w0.5: v7@26.598,48.414 28.972,46.04 36.438,46.04 J10.11@46.165,36.313
MCU_nFAULT: J10.3 U1.43 | length 31.8
  Top Layer w0.326: U1.43@24.162,42.814 24.175,42.827 24.175,43.644 24.638,44.107 v7@24.638,44.136
  Bottom Layer w0.326: v7(24.669,44.112) 24.669,50.452 25.691,51.474 41.176,51.474 46.144,46.506 J10.3@46.144,46.495
MCU_STATUS: D1.2 U1.26 | length 14.7
  Top Layer w0.25: v1(8.959,53.818) 8.959,53.846 9.546,54.434 D1.2@9.546,54.494 ; U1.26@17.212,47.764 17.237,47.789 18.263,47.789 v1(18.736,48.262)
  Mid-Layer 1 w0.25: v1(8.959,53.818) 14.515,48.262 v1(18.736,48.262)
NetC3_2: C3.2 U1.32 | length 2.3
  Top Layer w0.152: C3.2@15.558,43.688 16.101,44.231 16.101,44.492 16.299,44.69 17.138,44.69 U1.32@17.212,44.764
NetC8_1: C8.1 R14.1 R15.2 XDS1.70 | length 10
  Top Layer w0.203: R14.1@12.929,29.535 12.941,29.522 14.477,29.522 R15.2@14.49,29.509 ; 13.769,29.482 13.769,28.019 16.006,28.019 16.561,27.463 16.561,24.534 16.308,24.28 XDS1.70@15.607,24.28
NetC12_1: C12.1 R22.1 XDS1.68 | length 3.4
  Top Layer w0.203: R22.1@13.529,23.27 C12.1@13.529,24.78 ; C12.1@13.825,24.976 13.827,24.978 14.097,24.978 14.206,25.088 XDS1.68@15.619,25.088
NetC16_1: C16.1 XDS1.88 Y2.3 | length 7
  Top Layer w0.203: C16.1@12.329,19.488 11.753,19.488 11.753,18.535 11.307,18.089 11.307,17.939 11.806,17.44 12.013,17.233 12.013,17.224 12.156,17.08 XDS1.88@15.607,17.08
NetC17_1: C17.1 C18.1 IC3.3 R28.1 XDS1.9 | length 8.3
  Top Layer w0.203: XDS1.9@31.019,17.088 31.021,17.09 31.721,17.09 32.489,17.858 32.489,18.162 33.456,19.128 R28.1@33.556,19.128 C18.1@33.556,20.651 C17.1@33.556,22.174 33.556,22.967 33.618,23.029 33.618,23.574 33.717,23.672 IC3.3@33.892,23.672
NetC23_1: C23.1 XDS1.89 Y2.1 | length 5
  Top Layer w0.203: C23.1@13.539,14.113 13.439,14.113 13.241,14.312 13.241,15.608 Y2.1@13.01,15.839 13.01,15.939 13.751,16.68 XDS1.89@15.607,16.68
NetC24_1: C24.1 R24.2 XDS1.96 | length 5.5
  Top Layer w0.203: R24.2@13.401,10.174 13.44,10.135 C24.1@14.88,10.135 14.88,10.235 15.56,10.916 XDS1.96@15.56,13.883
NetC27_1: C27.1 C28.1 C29.1 XDS1.87 XDS1.115 | length 17.8
  Top Layer w0.203: XDS1.87@15.619,17.488 16.78,17.49 ; C27.1@22.919,10.149 C28.1@24.452,10.149 ; 24.307,14.467 24.307,14.465 24.755,14.017 24.755,13.596 24.309,13.15 24.309,12.382 XDS1.115@24.307,12.38 24.307,11.198 24.452,11.053 C28.1@24.452,10.149 ; C29.1@25.985,10.149 C28.1@24.452,10.149
  Top Layer w0.508: 16.78,17.49 21.285,17.49 24.307,14.467
NetC32_1: C32.1 U4.4 | length 4.6
  Top Layer w0.5: U4.4@90.628,22.737 U4.4@91.012,22.737 ; U4.4@91.001,22.787 91.032,22.757 U4.4@91.012,22.737 ; C32.1@91.619,19.012 91.338,19.293 91.338,22.737 U4.4@91.012,22.737
NetD1_1: D1.1 R1.2 | length 3.4
  Top Layer w0.152: R1.2@4.745,54.525 6.222,54.525 6.413,54.716 7.764,54.716 D1.1@7.996,54.484
NetD2_1: D2.1 R2.2 | length 3.2
  Top Layer w0.152: R2.2@4.692,51.778 7.811,51.778 D2.1@7.872,51.839
NetD3_1: D3.1 R3.2 | length 4.8
  Top Layer w0.152: R3.2@4.674,48.797 4.699,48.797 5.335,49.432 5.347,49.432 5.347,49.559 5.75,49.962 7.643,49.962 7.732,49.872 7.732,49.14 D3.1@8.014,48.858
NetD4_1: D4.1 R31.1 | length 28.8
  Top Layer w0.203: v2(7.813,11.19) 7.832,11.19 8.073,10.949 D4.1@8.753,10.949 ; v2(32.724,10.434) R31.1@33.59,10.434
  Bottom Layer w0.203: v2(7.813,11.19) 7.838,11.19 8.085,11.438 11.07,11.438 11.182,11.325 11.361,11.325 13.185,9.501 27.845,9.501 29.637,11.292 31.866,11.292 v2(32.724,10.434)
NetD5_1: D5.1 R27.1 | length 22.9
  Top Layer w0.203: v2(9.769,10.835) 10.721,10.835 D5.1@10.785,10.899 ; v2(29.632,10.428) 29.635,10.431 30.423,10.431 R27.1@30.426,10.434
  Bottom Layer w0.203: v2(9.769,10.835) 10.328,10.276 11.839,10.276 12.97,9.145 28.349,9.145 v2(29.632,10.428)
NetD6_1: D6.1 R34.2 | length 3.5
  Top Layer w0.328: R34.2@56.167,57.604 R34.2@56.355,57.791 ; R34.2@56.312,57.835 56.392,57.915 R34.2@56.484,57.915 58.265,57.915 D6.1@59.133,58.782
NetD7_1: D7.1 J7.2 | length 8.5
  Top Layer w2: J7.2@69.766,37.104 J7.2@69.737,37.133 69.766,37.162 70.931,37.162 73.913,40.144 73.913,41.06 74.098,41.244 74.098,42.16 74.318,42.381 D7.1@74.915,42.381
NetD7_2: D7.2 R50.2 R51.1 | length 6.2
  Top Layer w1.5: R50.2@73.471,32.119 74.982,32.119 R51.1@76.357,32.119
  Top Layer w2.5: 74.982,32.119 74.982,35.399 D7.2@75.003,35.42
NetD13_1: D13.1 R77.2 | length 2.1
  Top Layer w0.326: D13.1@133.815,64.916 133.81,64.912 133.81,62.906 R77.2@133.852,62.864
NetD14_1: D14.1 R78.2 | length 2.2
  Top Layer w0.326: D14.1@133.819,51.33 133.859,51.29 133.859,49.152 R78.2@133.849,49.142
NetD15_1: D15.1 R79.2 | length 2
  Top Layer w0.326: R79.2@133.67,35.015 133.698,35.043 133.698,36.974 D15.1@133.692,36.98
NetD16_1: D16.1 R80.2 | length 2
  Top Layer w0.326: D16.1@133.716,23.165 R80.2@133.716,21.215 133.716,21.168 R80.2@133.735,21.149
NetD17_1: D17.1 Q2.1 R81.1 | length 6.6
  Top Layer w0.5: D17.1@132.357,6.979 132.407,6.929 132.633,6.929 132.663,6.898 133.211,6.898 134.278,6.898 134.295,6.915 134.303,6.908 R81.1@134.303,6.898 ; 133.117,6.898 133.211,6.805 133.211,3.905 134.254,2.861 Q2.1@134.254,2.811
NetD18_1: D18.1 Q2.3 | length 2.7
  Top Layer w0.5: Q2.3@135.204,4.811 135.204,4.861 135.354,5.011 135.404,5.011 135.597,5.204 137.596,5.204 D18.1@137.699,5.101
NetJ6_1: J6.1 R45.2 | length 2.8
  Top Layer w0.5: R45.2@78.983,64.778 78.99,64.784 81.76,64.784 J6.1@81.766,64.79
NetJ6_3: J6.3 R46.2 | length 2.8
  Top Layer w0.5: R46.2@78.991,62.205 79.014,62.227 81.744,62.227 J6.3@81.766,62.25
NetJ6_5: J6.5 R47.2 | length 2.9
  Top Layer w0.5: R47.2@78.937,59.63 78.977,59.67 81.726,59.67 J6.5@81.766,59.71
NetJ6_7: J6.7 R48.2 | length 2.9
  Top Layer w0.5: R48.2@78.902,57.05 78.962,57.11 81.706,57.11 J6.7@81.766,57.17
NetJ6_9: J6.9 R49.2 | length 2.9
  Top Layer w0.5: R49.2@78.937,54.493 79.005,54.562 81.698,54.562 J6.9@81.766,54.63
NetJ8_2: J8.2 R52.1 | length 5.5
  Top Layer w2: J8.2@85.011,37.131 85.105,37.131 86.152,36.084 R52.1@86.152,32.119
NetJ9_2: J9.2 R53.2 | length 2.8
  Top Layer w0.5: R53.2@78.821,19.881 78.864,19.924 81.535,19.924 J9.2@81.565,19.894
NetJ9_4: J9.4 R54.2 | length 2.8
  Top Layer w0.5: R54.2@78.821,17.487 78.85,17.457 81.558,17.457 J9.4@81.612,17.404
NetJ9_6: J9.6 R55.2 | length 2.8
  Top Layer w0.5: R55.2@78.821,14.894 78.824,14.891 81.572,14.891 J9.6@81.58,14.899
NetJ9_8: J9.8 R56.2 | length 2.8
  Top Layer w0.5: R56.2@78.858,12.41 78.89,12.379 81.431,12.379 J9.8@81.588,12.221
NetJ9_10: J9.10 R57.2 | length 2.7
  Top Layer w0.5: R57.2@78.835,9.777 78.85,9.792 81.474,9.792 J9.10@81.506,9.824
NetJ9_12: J9.12 R58.2 | length 2.6
  Top Layer w0.326: R58.2@78.821,7.19 78.86,7.229 81.365,7.229 J9.12@81.376,7.239
NetJ9_14: J9.14 R59.2 | length 2.7
  Top Layer w0.5: R59.2@78.821,4.65 78.86,4.689 81.505,4.689 J9.14@81.529,4.713
NetQ2_2: Q2.2 R82.2 | length 6.3
  Top Layer w0.326: R82.2@131.45,2.984 R82.2@131.59,3.124
  Top Layer w0.5: R82.2@131.59,3.124 131.59,3.099 132.913,1.776 135.919,1.776 136.004,1.861 136.004,2.611 136.207,2.814 Q2.2@136.212,2.814
NetQ4_4: Q4.4 U4.6 | length 13.7
  Top Layer w0.5: v4@94.581,24.467 94.611,24.437 94.611,24.393 v4(94.581,24.363) 94.876,24.068 96.39,24.068 U4.6@96.401,24.057 ; Q4.4@103.404,24.03 103.983,24.03 104.547,24.594 v4(104.618,24.594)
  Mid-Layer 1 w0.5: v4(94.581,24.363) 104.387,24.363 v4(104.618,24.594)
NetR16_2: R16.2 XDS1.59 | length 2.2
  Top Layer w0.203: R16.2@18.119,29.482 18.219,29.482 19.117,28.583 XDS1.59@19.117,27.79
NetR18_1: R18.1 XDS1.61 | length 26.4
  Top Layer w0.203: v2(18.05,23.89) 17.999,23.941 17.999,26.283 18.306,26.59 XDS1.61@18.306,27.182 ; R18.1@34.768,31.452 34.868,31.452 35.066,31.253 35.066,30.8 v2(35.093,30.774)
  Bottom Layer w0.203: v2(18.05,23.89) 18.05,23.857 18.321,23.586 31.207,23.586 35.093,27.472 v2(35.093,30.774)
NetR19_1: R19.1 XDS1.62 | length 23.5
  Top Layer w0.203: v2(17.313,24.805) 17.356,24.848 17.356,25.146 17.592,25.382 17.592,26.38 17.906,26.693 XDS1.62@17.906,27.182 ; v2(34.534,29.224) 34.534,29.72 34.733,29.919 R19.1@34.768,29.919
  Bottom Layer w0.203: v2(17.313,24.805) 17.364,24.754 31.715,24.754 34.534,27.573 v2(34.534,29.224)
NetR20_1: R20.1 XDS1.63 | length 20.8
  Top Layer w0.203: v2(17.084,25.592) 17.084,26.481 17.507,26.904 XDS1.63@17.507,27.182 ; v2(33.798,27.624) 33.856,27.683 33.964,27.683 34.668,28.386 R20.1@34.768,28.386
  Bottom Layer w0.203: v2(17.084,25.592) 17.912,25.592 18.141,25.364 31.537,25.364 v2(33.798,27.624)
NetR21_1: R21.1 XDS1.60 | length 7.1
  Top Layer w0.203: R21.1@13.825,26.422 13.925,26.422 14.417,26.915 16.015,26.915 v2(16.018,26.913) ; v2(18.507,26.024) 18.507,26.106 18.707,26.307 XDS1.60@18.707,27.78
  Bottom Layer w0.203: v2(16.018,26.913) 16.491,26.439 16.956,26.439 17.371,26.024 v2(18.507,26.024)
NetR27_2: R27.2 XDS1.4 | length 6.7
  Top Layer w0.203: XDS1.4@31.017,15.086 29.972,15.086 29.607,14.721 29.607,13.578 31.626,11.559 R27.2@31.626,10.434
NetR31_2: R31.2 XDS1.3 | length 7.3
  Top Layer w0.203: XDS1.3@30.409,14.68 30.307,14.68 29.988,14.361 29.988,13.756 32.321,11.422 33.701,11.422 34.69,10.434 R31.2@34.79,10.434
nFAULT: J10.4 R33.1 R34.1 TP11.1 U3.10 | length 93.1
  Top Layer w0.326: v4(101.567,36.681) 101.567,36.689 102.952,38.073 U3.10@103.999,38.073
  Top Layer w0.75: R34.1@54.804,57.937 54.867,58 54.867,60.867 R33.1@54.85,60.884 ; R33.1@54.85,60.964 54.955,60.964 54.975,60.984 54.975,61.597 55.678,62.3 v1(55.678,62.303)
  Mid-Layer 1 w0.5: J10.4@48.742,46.447 48.786,46.404 TP11.1@55.608,46.404
  Mid-Layer 1 w0.75: TP11.1@55.608,46.427 55.758,46.277 v1(60.937,46.277)
  Mid-Layer 2 w0.75: TP11.1@55.663,46.36 55.663,60.422 55.678,60.437 v1(55.678,62.303) ; v1(60.743,32.513) 60.743,46.08 60.937,46.274 v1(60.937,46.277)
  Bottom Layer w0.75: v1(60.743,32.513) 76.242,32.513 77.086,31.668 96.555,31.668 v4(101.567,36.681)
OUT1: C34.2 D9.2 J1.1 R77.1 TP17.1 U3.17 | length 6
  Top Layer w0.326: U3.17@109.285,41.982 112.371,41.982 114.159,43.77 114.159,43.812 ; D9.2@128.97,60.833 D9.2@129.211,60.592
OUT2: C35.2 D10.2 J2.1 R78.1 TP18.1 U3.16 | length 4.4
  Top Layer w0.326: U3.16@109.285,41.332 113.572,41.332 113.643,41.402
OUT3: C36.2 D11.2 J3.1 R79.1 TP19.1 U3.15 | length 3.5
  Top Layer w0.326: U3.15@109.285,40.682 112.701,40.682 112.742,40.64
OUT4: C37.2 D12.2 J4.1 R80.1 TP22.1 U3.14 | length 5.8
  Top Layer w0.326: U3.14@109.285,40.032 114.414,40.032 114.737,39.709 114.737,39.515
PA0: J12.2 U1.33 | length 29.6
  Top Layer w0.326: v2(18.693,41.788) 18.71,41.788 19.162,42.24 U1.33@19.162,42.814
  Mid-Layer 1 w0.5: J12.2@7.757,63.252 7.934,63.076 11.885,63.076 v1(11.906,63.055)
  Bottom Layer w0.5: J12.2@8.196,63.121 8.196,63.104 J12.2@8.224,63.076 ; v1(11.906,63.055) 13.134,61.827 13.134,47.669 18.692,42.111 v2(18.693,41.788) v2(18.693,41.788)
PA1: J12.1 U1.34 | length 28.1
  Top Layer w0.326: v2(17.813,40.841) 17.847,40.806 17.97,40.806 18.108,40.667 18.378,40.667 19.649,41.939 19.649,42.801 U1.34@19.662,42.814
  Bottom Layer w0.5: J12.1@7.56,60.728 7.693,60.595 7.693,49.789 16.642,40.841 v2(17.813,40.841)
PB10: J13.1 U1.62 | length 29
  Top Layer w0.326: U1.62@28.612,51.264 31.408,51.264 v1(33.282,53.138)
  Mid-Layer 1 w0.5: J13.1@16.992,60.742 17.059,60.675 32.729,60.675 33.234,60.169 v1(33.264,60.169)
  Mid-Layer 2 w0.5: v1(33.264,60.169) 33.282,60.151 v1(33.282,53.138)
PB11: J13.2 U1.63 | length 28.4
  Top Layer w0.326: U1.63@28.612,51.764 30.258,51.764 v1(31.704,53.21)
  Mid-Layer 1 w0.5: J13.2@16.92,63.068 17.066,63.215 31.419,63.215 31.702,62.932 v1(31.732,62.932)
  Mid-Layer 2 w0.5: v1(31.704,53.21) 31.704,62.904 v1(31.732,62.932)
PB12: J13.3 U1.64 | length 28.4
  Top Layer w0.326: U1.64@28.612,52.264 29.186,52.264 30.344,53.421 v1(30.344,53.47)
  Mid-Layer 1 w0.5: J13.3@17.008,65.8 17.053,65.755 30.157,65.755 30.407,66.005 v1(30.437,66.005)
  Mid-Layer 2 w0.326: v1@30.306,65.837 v1@30.344,65.8
  Mid-Layer 2 w0.5: v1@30.306,65.837 30.306,65.874 v1(30.437,66.005) ; v1(30.344,53.47) v1@30.344,65.8
PB13: J13.4 U1.1 | length 23.3
  Top Layer w0.326: v1(26.092,55.627) 26.092,55.601 26.649,55.044 26.649,54.227 U1.1@26.662,54.214
  Mid-Layer 1 w0.326: J13.4@16.992,68.263 17.017,68.287 25.862,68.287 v1(25.869,68.28)
  Mid-Layer 2 w0.326: v1(25.869,68.28) 25.869,68.162 26.092,67.94 v1(26.092,55.627)
PB24: J12.4 U1.23 | length 30.9
  Top Layer w0.326: U1.23@17.212,49.264 18.565,49.264 v2(18.879,49.579)
  Mid-Layer 1 w0.5: J12.4@7.746,68.288 7.782,68.324 15.265,68.324 v1(15.271,68.319)
  Mid-Layer 2 w0.5: v1(15.271,68.319) 15.271,59.628 15.853,59.046 15.853,50.355 16.628,49.579 v2(18.879,49.579)
PB25: J12.3 U1.27 | length 30.2
  Top Layer w0.326: U1.27@17.212,47.264 17.225,47.277 19.015,47.277 v2(19.042,47.303)
  Mid-Layer 1 w0.5: J12.3@7.713,65.843 7.824,65.732 14.146,65.732 v1(14.167,65.711)
  Bottom Layer w0.5: v1(14.167,65.711) 14.167,57.754 14.774,57.147 14.774,49.19 16.66,47.303 v2(19.042,47.303)
PI_IN: C33.1 C41.2 C42.2 C43.1 C44.2 C45.1 L1.1 Q4.5 Q4.6 Q4.7 Q4.8 Q4.9@101.543,27.928 U4.8
POT_IN1: R9.2 U1.14 | length 80.6
  Top Layer w0.326: U1.14@20.162,54.214 20.175,54.201 20.175,53.164 v2(21.71,51.629)
  Mid-Layer 1 w0.75: v2(21.71,51.629) 22.082,52 91.97,52 95.144,55.175 R9.2@97.644,55.175
POT_IN2: R10.2 U1.15 | length 92.2
  Top Layer w0.326: v2(19.357,55.718) 19.357,55.669 19.649,55.377 19.649,54.227 U1.15@19.662,54.214
  Mid-Layer 1 w1: v4(19.151,67.099) 51.547,67.099 52.192,67.744 95.954,67.744 96.049,67.838 96.221,67.838 97.439,69.056 R10.2@97.48,69.056
  Mid-Layer 2 w1: v4(19.151,67.099) 19.151,55.929 v2@19.33,55.749
POT_IN3: R11.2 U1.16 | length 112.4
  Top Layer w0.326: U1.16@19.162,54.214 19.162,52.784 19.48,52.467 v2(19.499,52.467) v2@19.499,52.453
  Mid-Layer 1 w0.326: v2(19.499,52.467) 20.263,53.232 v1(28.655,53.232)
  Mid-Layer 1 w1: v1@30.613,69.565 31.331,70.284 104.742,70.284 105.969,69.056 R11.2@113.781,69.056
  Mid-Layer 2 w0.75: v1(28.655,53.232) 29.234,53.81 29.234,68.072 v1(30.592,69.431)
POT_IN4: R12.2 U1.19 | length 101
  Top Layer w0.326: U1.19@17.212,51.264 19.104,51.264 v2(19.645,50.723)
  Mid-Layer 1 w0.75: v2(19.645,50.723) 26.037,50.723 26.412,51.098 113.286,51.098 113.726,51.537 R12.2@113.726,55.444
PVDD_ADC: R4.1 R5.2 U1.10 | length 9.4
  Top Layer w0.326: R4.1@17.334,57.05 17.928,57.05 17.984,56.994 19.321,56.994 19.481,56.834 21.02,56.834 ; U1.10@22.162,54.214 22.162,55.692 21.02,56.834 ; R5.2@23.36,57.4 21.585,57.4 21.02,56.834
REF_TARGET_VCC: XDS1.120
REV_ID1: R35.2 R36.1 U1.9 | length 73.6
  Top Layer w0.326: U1.9@22.662,54.214 22.662,55.855 v5(23.226,56.419)
  Top Layer w0.5: R36.1@56.609,21.855 56.666,21.912 56.666,22.509 ; R35.2@56.67,23.162 56.666,23.159 56.666,22.509 ; v1(58.192,22.827) 58.121,22.827 57.804,22.509 56.666,22.509
  Mid-Layer 1 w0.5: v5(23.226,56.419) 57.574,56.419 v1(58.168,55.825)
  Mid-Layer 2 w0.5: v1(58.168,55.825) 58.168,22.851 v1(58.192,22.827)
